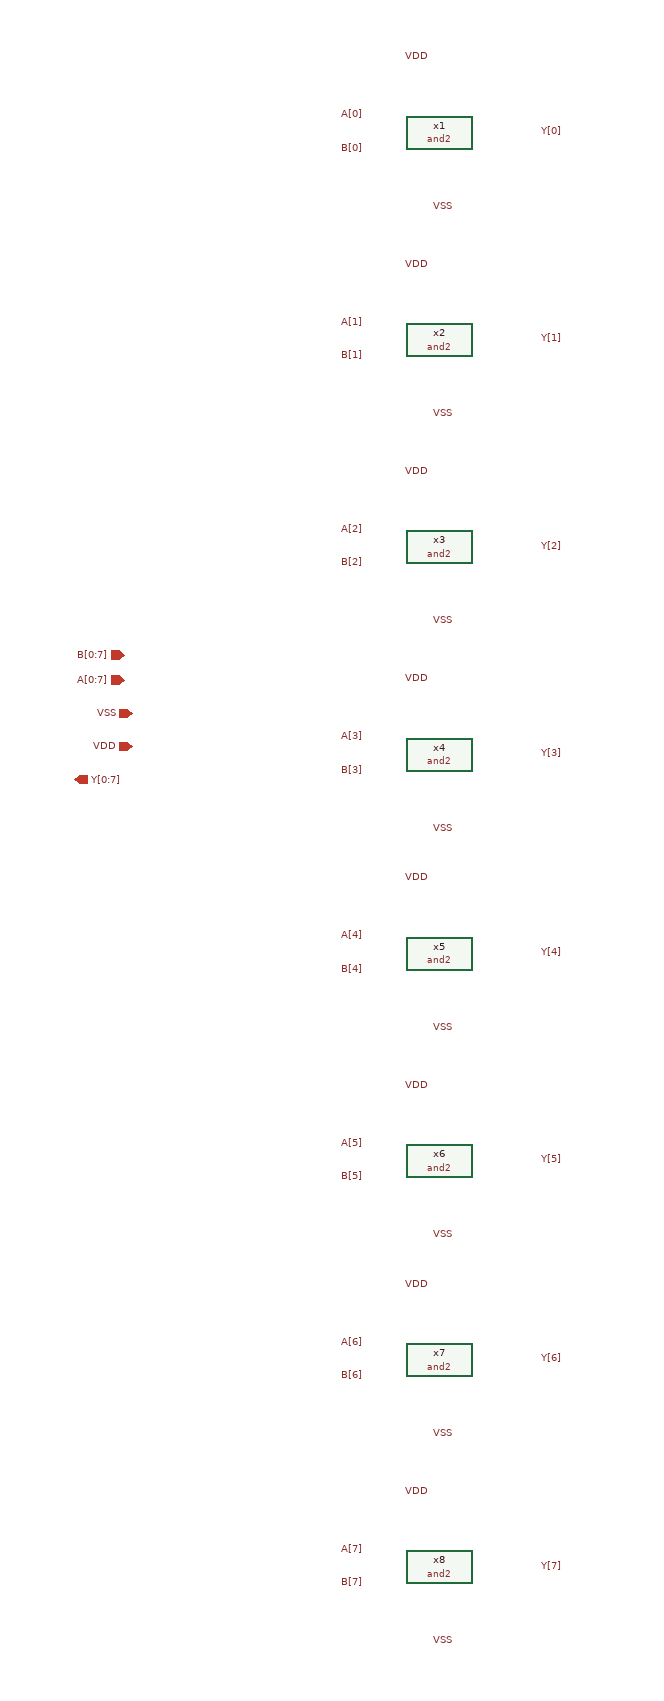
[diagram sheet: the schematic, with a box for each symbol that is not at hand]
v {xschem version=3.1.0 file_version=1.2 }
G {}
K {}
V {}
S {}
E {}
C {and2.sym} 50 -860 0 0 {name=x1}
C {and2.sym} 50 -610 0 0 {name=x2}
C {and2.sym} 50 -360 0 0 {name=x3}
C {and2.sym} 50 -110 0 0 {name=x4}
C {and2.sym} 50 130 0 0 {name=x5}
C {and2.sym} 50 380 0 0 {name=x6}
C {and2.sym} 50 620 0 0 {name=x7}
C {and2.sym} 50 870 0 0 {name=x8}
C {devices/ipin.sym} -330 -200 0 0 {name=p3 lab=A[0:7]}
C {devices/opin.sym} -390 -80 0 0 {name=p9 lab=Y[0:7]}
C {devices/iopin.sym} -320 -160 2 0 {name=p6 lab=VSS}
C {devices/iopin.sym} -320 -120 2 0 {name=p7 lab=VDD}
C {devices/lab_pin.sym} 40 -950 1 0 {name=l3 sig_type=std_logic lab=VDD}
C {devices/lab_pin.sym} 40 -700 1 0 {name=l1 sig_type=std_logic lab=VDD}
C {devices/lab_pin.sym} 40 -450 1 0 {name=l2 sig_type=std_logic lab=VDD}
C {devices/lab_pin.sym} 40 -200 1 0 {name=l4 sig_type=std_logic lab=VDD}
C {devices/lab_pin.sym} 40 40 1 0 {name=l5 sig_type=std_logic lab=VDD}
C {devices/lab_pin.sym} 40 290 1 0 {name=l6 sig_type=std_logic lab=VDD}
C {devices/lab_pin.sym} 40 530 1 0 {name=l7 sig_type=std_logic lab=VDD}
C {devices/lab_pin.sym} 40 780 1 0 {name=l8 sig_type=std_logic lab=VDD}
C {devices/ipin.sym} -330 -230 0 0 {name=p1 lab=B[0:7]}
C {devices/lab_pin.sym} -40 -880 0 0 {name=l12 sig_type=std_logic lab=A[0]}
C {devices/lab_pin.sym} -40 -630 0 0 {name=l9 sig_type=std_logic lab=A[1]}
C {devices/lab_pin.sym} -40 -380 0 0 {name=l10 sig_type=std_logic lab=A[2]}
C {devices/lab_pin.sym} -40 -130 0 0 {name=l11 sig_type=std_logic lab=A[3]}
C {devices/lab_pin.sym} -40 110 0 0 {name=l13 sig_type=std_logic lab=A[4]}
C {devices/lab_pin.sym} -40 360 0 0 {name=l14 sig_type=std_logic lab=A[5]}
C {devices/lab_pin.sym} -40 600 0 0 {name=l15 sig_type=std_logic lab=A[6]}
C {devices/lab_pin.sym} -40 850 0 0 {name=l16 sig_type=std_logic lab=A[7]}
C {devices/lab_pin.sym} -40 -840 0 0 {name=l18 sig_type=std_logic lab=B[0]}
C {devices/lab_pin.sym} -40 -590 0 0 {name=l19 sig_type=std_logic lab=B[1]}
C {devices/lab_pin.sym} -40 -340 0 0 {name=l20 sig_type=std_logic lab=B[2]}
C {devices/lab_pin.sym} -40 -90 0 0 {name=l21 sig_type=std_logic lab=B[3]}
C {devices/lab_pin.sym} -40 150 0 0 {name=l22 sig_type=std_logic lab=B[4]}
C {devices/lab_pin.sym} -40 400 0 0 {name=l23 sig_type=std_logic lab=B[5]}
C {devices/lab_pin.sym} -40 640 0 0 {name=l24 sig_type=std_logic lab=B[6]}
C {devices/lab_pin.sym} -40 890 0 0 {name=l17 sig_type=std_logic lab=B[7]}
C {devices/lab_pin.sym} 40 -770 2 0 {name=l25 sig_type=std_logic lab=VSS}
C {devices/lab_pin.sym} 40 -520 2 0 {name=l27 sig_type=std_logic lab=VSS}
C {devices/lab_pin.sym} 40 -270 2 0 {name=l28 sig_type=std_logic lab=VSS}
C {devices/lab_pin.sym} 40 -20 2 0 {name=l29 sig_type=std_logic lab=VSS}
C {devices/lab_pin.sym} 40 220 2 0 {name=l30 sig_type=std_logic lab=VSS}
C {devices/lab_pin.sym} 40 470 2 0 {name=l31 sig_type=std_logic lab=VSS}
C {devices/lab_pin.sym} 40 710 2 0 {name=l32 sig_type=std_logic lab=VSS}
C {devices/lab_pin.sym} 40 960 2 0 {name=l33 sig_type=std_logic lab=VSS}
C {devices/lab_pin.sym} 170 -860 2 0 {name=l26 sig_type=std_logic lab=Y[0]}
C {devices/lab_pin.sym} 170 -610 2 0 {name=l34 sig_type=std_logic lab=Y[1]}
C {devices/lab_pin.sym} 170 -360 2 0 {name=l35 sig_type=std_logic lab=Y[2]}
C {devices/lab_pin.sym} 170 -110 2 0 {name=l36 sig_type=std_logic lab=Y[3]}
C {devices/lab_pin.sym} 170 130 2 0 {name=l37 sig_type=std_logic lab=Y[4]}
C {devices/lab_pin.sym} 170 380 2 0 {name=l38 sig_type=std_logic lab=Y[5]}
C {devices/lab_pin.sym} 170 620 2 0 {name=l39 sig_type=std_logic lab=Y[6]}
C {devices/lab_pin.sym} 170 870 2 0 {name=l40 sig_type=std_logic lab=Y[7]}
